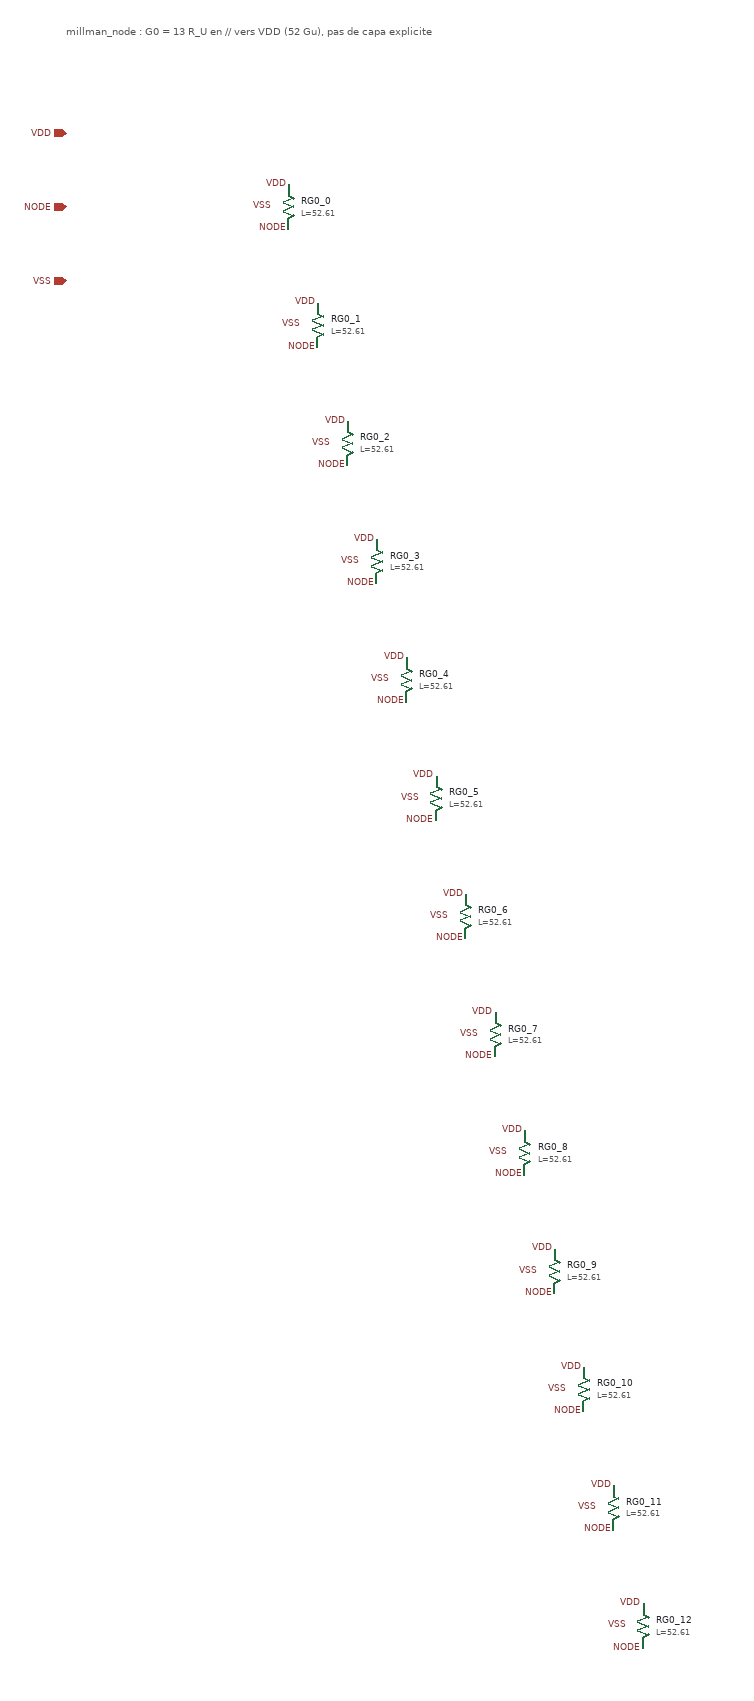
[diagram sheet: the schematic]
v {xschem version=3.4.8RC file_version=1.2}
G {}
K {}
V {}
S {}
E {}
C {iopin.sym} -300 0 0 0 {name=p_NODE lab=NODE}
C {iopin.sym} -300 -100 0 0 {name=p_VDD lab=VDD}
C {iopin.sym} -300 100 0 0 {name=p_VSS lab=VSS}
C {sky130_fd_pr/res_xhigh_po_0p35.sym} 0 0 0 0 {name=RG0_0 L=52.61 model=res_xhigh_po_0p35 spiceprefix=X mult=1}
C {lab_pin.sym} 0 -30 0 0 {name=l1 sig_type=std_logic lab=VDD}
C {lab_pin.sym} 0 30 0 0 {name=l2 sig_type=std_logic lab=NODE}
C {lab_pin.sym} -20 0 0 0 {name=l3 sig_type=std_logic lab=VSS}
C {sky130_fd_pr/res_xhigh_po_0p35.sym} 40 160 0 0 {name=RG0_1 L=52.61 model=res_xhigh_po_0p35 spiceprefix=X mult=1}
C {lab_pin.sym} 40 130 0 0 {name=l4 sig_type=std_logic lab=VDD}
C {lab_pin.sym} 40 190 0 0 {name=l5 sig_type=std_logic lab=NODE}
C {lab_pin.sym} 20 160 0 0 {name=l6 sig_type=std_logic lab=VSS}
C {sky130_fd_pr/res_xhigh_po_0p35.sym} 80 320 0 0 {name=RG0_2 L=52.61 model=res_xhigh_po_0p35 spiceprefix=X mult=1}
C {lab_pin.sym} 80 290 0 0 {name=l7 sig_type=std_logic lab=VDD}
C {lab_pin.sym} 80 350 0 0 {name=l8 sig_type=std_logic lab=NODE}
C {lab_pin.sym} 60 320 0 0 {name=l9 sig_type=std_logic lab=VSS}
C {sky130_fd_pr/res_xhigh_po_0p35.sym} 120 480 0 0 {name=RG0_3 L=52.61 model=res_xhigh_po_0p35 spiceprefix=X mult=1}
C {lab_pin.sym} 120 450 0 0 {name=l10 sig_type=std_logic lab=VDD}
C {lab_pin.sym} 120 510 0 0 {name=l11 sig_type=std_logic lab=NODE}
C {lab_pin.sym} 100 480 0 0 {name=l12 sig_type=std_logic lab=VSS}
C {sky130_fd_pr/res_xhigh_po_0p35.sym} 160 640 0 0 {name=RG0_4 L=52.61 model=res_xhigh_po_0p35 spiceprefix=X mult=1}
C {lab_pin.sym} 160 610 0 0 {name=l13 sig_type=std_logic lab=VDD}
C {lab_pin.sym} 160 670 0 0 {name=l14 sig_type=std_logic lab=NODE}
C {lab_pin.sym} 140 640 0 0 {name=l15 sig_type=std_logic lab=VSS}
C {sky130_fd_pr/res_xhigh_po_0p35.sym} 200 800 0 0 {name=RG0_5 L=52.61 model=res_xhigh_po_0p35 spiceprefix=X mult=1}
C {lab_pin.sym} 200 770 0 0 {name=l16 sig_type=std_logic lab=VDD}
C {lab_pin.sym} 200 830 0 0 {name=l17 sig_type=std_logic lab=NODE}
C {lab_pin.sym} 180 800 0 0 {name=l18 sig_type=std_logic lab=VSS}
C {sky130_fd_pr/res_xhigh_po_0p35.sym} 240 960 0 0 {name=RG0_6 L=52.61 model=res_xhigh_po_0p35 spiceprefix=X mult=1}
C {lab_pin.sym} 240 930 0 0 {name=l19 sig_type=std_logic lab=VDD}
C {lab_pin.sym} 240 990 0 0 {name=l20 sig_type=std_logic lab=NODE}
C {lab_pin.sym} 220 960 0 0 {name=l21 sig_type=std_logic lab=VSS}
C {sky130_fd_pr/res_xhigh_po_0p35.sym} 280 1120 0 0 {name=RG0_7 L=52.61 model=res_xhigh_po_0p35 spiceprefix=X mult=1}
C {lab_pin.sym} 280 1090 0 0 {name=l22 sig_type=std_logic lab=VDD}
C {lab_pin.sym} 280 1150 0 0 {name=l23 sig_type=std_logic lab=NODE}
C {lab_pin.sym} 260 1120 0 0 {name=l24 sig_type=std_logic lab=VSS}
C {sky130_fd_pr/res_xhigh_po_0p35.sym} 320 1280 0 0 {name=RG0_8 L=52.61 model=res_xhigh_po_0p35 spiceprefix=X mult=1}
C {lab_pin.sym} 320 1250 0 0 {name=l25 sig_type=std_logic lab=VDD}
C {lab_pin.sym} 320 1310 0 0 {name=l26 sig_type=std_logic lab=NODE}
C {lab_pin.sym} 300 1280 0 0 {name=l27 sig_type=std_logic lab=VSS}
C {sky130_fd_pr/res_xhigh_po_0p35.sym} 360 1440 0 0 {name=RG0_9 L=52.61 model=res_xhigh_po_0p35 spiceprefix=X mult=1}
C {lab_pin.sym} 360 1410 0 0 {name=l28 sig_type=std_logic lab=VDD}
C {lab_pin.sym} 360 1470 0 0 {name=l29 sig_type=std_logic lab=NODE}
C {lab_pin.sym} 340 1440 0 0 {name=l30 sig_type=std_logic lab=VSS}
C {sky130_fd_pr/res_xhigh_po_0p35.sym} 400 1600 0 0 {name=RG0_10 L=52.61 model=res_xhigh_po_0p35 spiceprefix=X mult=1}
C {lab_pin.sym} 400 1570 0 0 {name=l31 sig_type=std_logic lab=VDD}
C {lab_pin.sym} 400 1630 0 0 {name=l32 sig_type=std_logic lab=NODE}
C {lab_pin.sym} 380 1600 0 0 {name=l33 sig_type=std_logic lab=VSS}
C {sky130_fd_pr/res_xhigh_po_0p35.sym} 440 1760 0 0 {name=RG0_11 L=52.61 model=res_xhigh_po_0p35 spiceprefix=X mult=1}
C {lab_pin.sym} 440 1730 0 0 {name=l34 sig_type=std_logic lab=VDD}
C {lab_pin.sym} 440 1790 0 0 {name=l35 sig_type=std_logic lab=NODE}
C {lab_pin.sym} 420 1760 0 0 {name=l36 sig_type=std_logic lab=VSS}
C {sky130_fd_pr/res_xhigh_po_0p35.sym} 480 1920 0 0 {name=RG0_12 L=52.61 model=res_xhigh_po_0p35 spiceprefix=X mult=1}
C {lab_pin.sym} 480 1890 0 0 {name=l37 sig_type=std_logic lab=VDD}
C {lab_pin.sym} 480 1950 0 0 {name=l38 sig_type=std_logic lab=NODE}
C {lab_pin.sym} 460 1920 0 0 {name=l39 sig_type=std_logic lab=VSS}
T {millman_node : G0 = 13 R_U en // vers VDD (52 Gu), pas de capa explicite} -300 -250 0 0 0.4 0.4 {}
